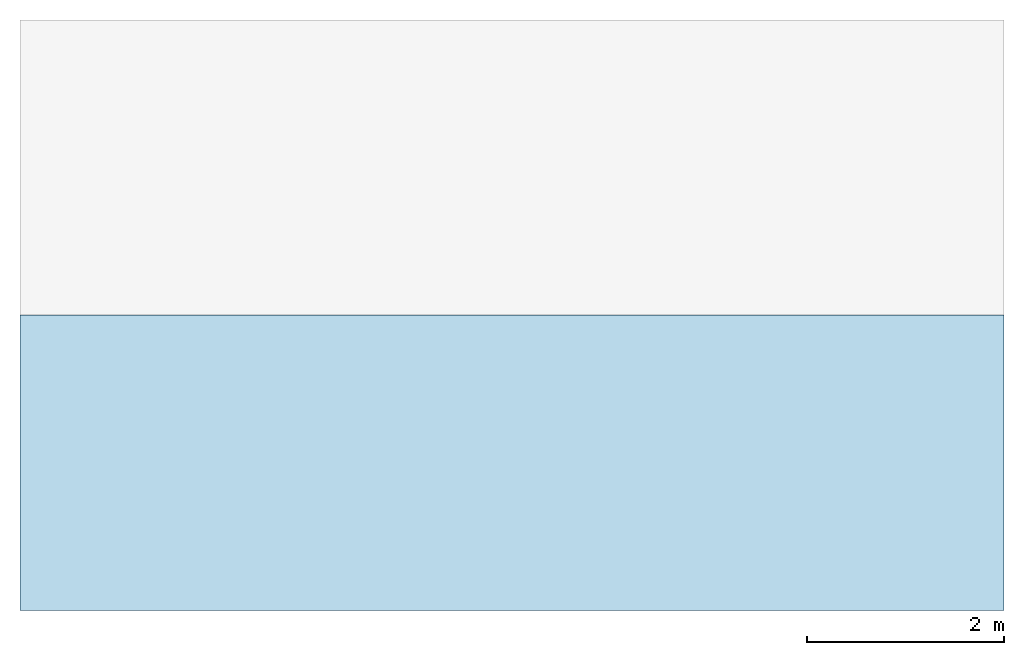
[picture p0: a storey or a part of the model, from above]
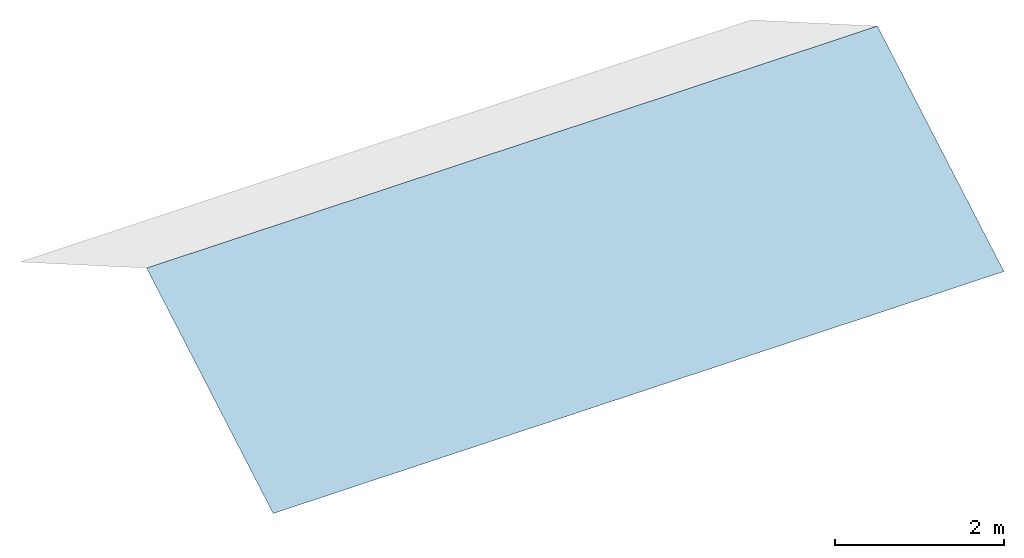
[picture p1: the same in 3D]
Properties of the parts of a building model (IFC4X3_ADD2)

# File
Description: StrechoStav Sketch IFC export
File name: Sk-obn-sedlov-strecha.ifc
Time: 2026-08-17T10:00:00Z
Organization: StrechoStav
Written by: StrechoStav Sketch 3.7.55
Made in: StrechoStav Sketch

# IfcProject: STRECHOSTAV_PROJECT, Skúšobná sedlová strecha
Description: StrechoStav Sketch BIM export; LongName: Skúšobná sedlová strecha
StrechoStav_ProjectData - Schema: strechostav-sketch-project-6; SchemaVersion: 6; Application: StrechoStav Sketch; ApplicationVersion: 3.7.55; ProjectId: ifc-test-project; PayloadEncoding: UTF-8 JSON; PayloadSha256: 6aeb4ea7a81c1e32eb3cb1a4cec82e20a06544cac115e883fd99c32776cfce77; PayloadChunkCount: 4; Payload0001: { "schema": "strechostav-sketch-project-10", "attic_height_m": 0.3, "roof_topology": { "schema_version": 3, "nodes": [ { "x": 0, "y": 0, "id": "A", "type": "FOOTPRINT", "locked": false }, { "x": 10, "y": 0, "id": "B", "type": "FOOTPRINT", "locked": false }, { "x": 10, "y": 6, "id": "C", "type": "FOOTPRINT", "locked": false }, { "x": 0, "y": 6, "id": "D", "type": "FOOTPRINT", "locked": false }, { "x": 0, "y": 3, "id": "L", "type": "FOOTPRINT", "locked": false }, { "x": 10, "y": 3, "id": "R", "type": "FOOTPRINT", "locked": false } ], "origin": { "lon": 18, "lat": 49 }, "edges": [ { "boundary": true, "note": "", "end_node_id": "B", "id": "AB", "start_node_id": "A", "source_id": "AB", "type": "EAVE", "locked": false }, { "boundary": true, "note": "", "end_node_id": "R", "id": "BR", "start_node_id": "B", "source_id": "BR", "type": "GABLE", "locked": false }, { "boundary": true, "note": "", "end_node_id": "D", "id": "CD", "start_node_id": "C", "source_id": "CD", "type": "EAVE", "locked": false }, { "boundary": true, "note": "", "end_node_id": "L", "id": "DL", "start_node_id": "D", "source_id": "DL", "type": "GABLE", "locked": false }, { "boundary": true, "note": "", "end_node_id": "A", "id": "LA", "start_node_id": "L", "source_id": "LA", "type": "GABLE", "locked": false }, { "boundary": true, "note": "", "end_node_id": "C", "id": "RC", "start_node_id": "R", "source_id": "RC", "type": "GABLE", "locked": false }, { "boundary": false, "note": "", "end_node_id": "R", "id": "RIDGE", "start_node_id": "L", "source_id": "RIDGE", "type": "RIDGE", "locked": false } ], "grid_rotation_deg": 0 }, "wall_height_m": 3, "objects": [ { "downspout_suppressed": false, "note": "", "direction_x": 0, "direction_y": 1, "center": { "lon": 18.000068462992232, "lat": 49.000013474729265 }, "downspout_termination": "ELBOW_72", "width_mm": 780, "downspout_automatic": false, "type": "ROOF_WINDOW", "dormer_overhang_mm": 250, "rotation_deg": 0, "dormer_type": "GABLE", "superstructure_height_m": 1.2,; Payload0002: "superstructure_slope_deg": 15, "chimney_height_manual": false, "attached_face_id": "face-105dda3c-4227-3e2c-8284-361fde8efe1c", "id": "window-1", "height_mm": 1180, "diameter_mm": 0, "value": 0 }, { "downspout_suppressed": false, "note": "", "direction_x": 0, "direction_y": 1, "center": { "lon": 18.000027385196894, "lat": 49.00004042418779 }, "downspout_termination": "ELBOW_72", "width_mm": 700, "downspout_automatic": false, "type": "CHIMNEY", "dormer_overhang_mm": 250, "rotation_deg": 0, "dormer_type": "GABLE", "superstructure_height_m": 1.2, "superstructure_slope_deg": 15, "chimney_height_manual": false, "attached_face_id": "face-7f29ebdd-5568-3a92-861d-d7df8271fc61", "id": "chimney-1", "height_mm": 700, "diameter_mm": 0, "value": 1.2 } ], "created_at": 1700000000000, "wall_footprint_parts": [], "underlay_meters_per_pixel": 0.01, "underlay_zoom": 1, "schema_version": 10, "map_type": "ZBGIS_ORTHO", "underlay_uri": "", "geometry_grid_origin_lat": 49, "updated_at": 1700000000000, "budget_vat_percent": 23, "roof_shape": "GABLE", "roof_graph": { "schema_version": 2, "components": [{ "face_ids": [], "id": "main", "label": "Hlavná strecha" }], "nodes": [ { "lock_z": false, "lock_x": false, "lock_y": false, "x": 0, "y": 0, "z": 0, "id": "A" }, { "lock_z": false, "lock_x": false, "lock_y": false, "x": 10, "y": 0, "z": 0, "id": "B" }, { "lock_z": false, "lock_x": false, "lock_y": false, "x": 10, "y": 6, "z": 0, "id": "C" }, { "lock_z": false, "lock_x": false, "lock_y": false, "x": 0, "y": 6, "z": 0, "id": "D" }, { "lock_z": false, "lock_x": false, "lock_y": false, "x": 0, "y": 3, "z": 0, "id": "L" }, { "lock_z": false, "lock_x": false, "lock_y": false, "x": 10, "y": 3, "z": 0, "id": "R" } ], "origin": { "lon": 18, "lat": 49 }, "edges": [ { "boundary": true, "note": "", "end_node_id": "B", "id": "AB", "start_node_id": "A", "semantic_role": "EAVE", "locked": false, "adjacent_face_ids": ["face-7f29ebdd-5568-3a92-861d-d7df8271fc61"] }, { "boundary": true, "note": "", "end_node_id": "R", "id": "BR", "start_node_id": "B", "semantic_role": "GABLE", "locked": false, "adjacent_face_ids": ["face-7f29ebdd-5568-3a92-861d-d7df8271fc61"] }; Payload0003: , { "boundary": true, "note": "", "end_node_id": "D", "id": "CD", "start_node_id": "C", "semantic_role": "EAVE", "locked": false, "adjacent_face_ids": ["face-105dda3c-4227-3e2c-8284-361fde8efe1c"] }, { "boundary": true, "note": "", "end_node_id": "L", "id": "DL", "start_node_id": "D", "semantic_role": "GABLE", "locked": false, "adjacent_face_ids": ["face-105dda3c-4227-3e2c-8284-361fde8efe1c"] }, { "boundary": true, "note": "", "end_node_id": "A", "id": "LA", "start_node_id": "L", "semantic_role": "GABLE", "locked": false, "adjacent_face_ids": ["face-7f29ebdd-5568-3a92-861d-d7df8271fc61"] }, { "boundary": true, "note": "", "end_node_id": "C", "id": "RC", "start_node_id": "R", "semantic_role": "GABLE", "locked": false, "adjacent_face_ids": ["face-105dda3c-4227-3e2c-8284-361fde8efe1c"] }, { "boundary": false, "note": "", "end_node_id": "R", "id": "RIDGE", "start_node_id": "L", "semantic_role": "RIDGE", "locked": false, "adjacent_face_ids": [ "face-105dda3c-4227-3e2c-8284-361fde8efe1c", "face-7f29ebdd-5568-3a92-861d-d7df8271fc61" ] } ], "edge_length_constraints": [], "faces": [ { "ordered_edge_ids": [ "CD", "DL", "RIDGE", "RC" ], "hole_node_id_loops": [], "component_id": "main", "underconstrained": false, "ordered_node_ids": [ "C", "D", "L", "R" ], "signed_area_m2": 30, "id": "face-105dda3c-4227-3e2c-8284-361fde8efe1c", "elevation_constraints": [] }, { "ordered_edge_ids": [ "AB", "BR", "RIDGE", "LA" ], "hole_node_id_loops": [], "component_id": "main", "underconstrained": false, "ordered_node_ids": [ "A", "B", "R", "L" ], "signed_area_m2": 30, "id": "face-7f29ebdd-5568-3a92-861d-d7df8271fc61", "elevation_constraints": [] } ], "grid_rotation_deg": 0, "drain_point_constraints": [], "dimensions": [] }, "slope_deg": 30, "id": "ifc-test-project", "lines": [], "last_google_map_type": "ZBGIS_ORTHO", "summary": { "perimeter_m": 33.856406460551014, "wall_end_m": 0, "superstructure_roof_area_m2": 0, "height_marks": 0, "superstructure_opening_area_m2": 0, "gable_m": 13.856406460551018, "hip_m": 0, "outer_gutter_corners_90": 0, "terraces": 0, "shafts": 0, "roof_area_m2": 69.28203230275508, "eave_m": 20, "machine_rooms": 0, "drains"; Payload0004: : 0, "gutter_hooks": 26, "chimneys": 1, "inner_gutter_corners_90": 0, "attic_m": 0, "downspout_clamps": 6, "vents": 0, "hatches": 0, "dormers": 0, "downspouts": 2, "slope_marks": 0, "roof_windows": 1, "footprint_area_m2": 60, "valley_m": 0, "pult_m": 0, "ridge_m": 10 }, "address": "Martin, Slovensko", "underlay_mime": "", "attic_width_m": 0.25, "underlay_center_x": -1, "center_lon": 18.9236, "underlay_center_y": -1, "underlay_origin_lon": 18.9236, "zoom": 19, "edge_types": {}, "geometry_grid_rotation_deg": 0, "selected_work_items": [], "center_lat": 49.0663, "wall_footprint": [ { "lon": 18, "lat": 49 }, { "lon": 18.000136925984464, "lat": 49 }, { "lon": 18.000136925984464, "lat": 49.00002694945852 }, { "lon": 18.000136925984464, "lat": 49.000053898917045 }, { "lon": 18, "lat": 49.000053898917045 }, { "lon": 18, "lat": 49.00002694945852 } ], "map_rotation_deg": 0, "polygon": [ { "lon": 18, "lat": 49 }, { "lon": 18.000136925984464, "lat": 49 }, { "lon": 18.000136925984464, "lat": 49.00002694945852 }, { "lon": 18.000136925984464, "lat": 49.000053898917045 }, { "lon": 18, "lat": 49.000053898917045 }, { "lon": 18, "lat": 49.00002694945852 } ], "underlay_origin_lat": 49.0663, "name": "Skúšobná sedlová strecha", "underlay_name": "", "wall_footprint_parts_signature": "", "geometry_grid_origin_lon": 18, "customer": "Žofia O'Connor" }

# IfcBuilding, Skúšobná sedlová strecha
LongName: Skúšobná sedlová strecha

# IfcBuildingStorey, Strecha
In: Skúšobná sedlová strecha
LongName: Strecha; Elevation: 3 m

# IfcChimney: CHIMNEY, Komín
In: Strecha
StrechoStav_Object - ObjectId: chimney-1; ObjectType: CHIMNEY; WidthMm: 700; HeightMm: 700; Value: 1.2; RotationDeg: 0; AttachedFaceId: face-7f29ebdd-5568-3a92-861d-d7df8271fc61; DirectionX: 0; DirectionY: 1; ChimneyHeightManual: no

# IfcOpeningElement: ROOF_WINDOW_OPENING, Otvor pre strešné okno window-1
In: Strecha
PredefinedType: OPENING

# IfcRoof: GABLE, Strecha
In: Strecha
PredefinedType: GABLE_ROOF
StrechoStav_Roof - ProjectId: ifc-test-project; RoofShape: GABLE; DefaultSlopeDeg: 30; WallHeightM: 3; OriginLatitude: 49; OriginLongitude: 18; GraphEdgesJson: [{"id":"AB","role":"EAVE","start":"A","end":"B"}, {"id":"BR","role":"GABLE","start":"B","end":"R"}, {"id":"CD","role":"EAVE","start":"C","end":"D"}, {"id":"DL","role":"GABLE","start":"D","end":"L"}, {"id":"LA","role":"GABLE","start":"L","end":"A"}, {"id":"RC","role":"GABLE","start":"R","end":"C"}, {"id":"RIDGE","role":"RIDGE","start":"L","end":"R"}]
Qto_RoofBaseQuantities - GrossArea: 69.282 m2; NetArea: 69.282 m2; ProjectedArea: 60 m2

# IfcSlab: ROOF_FACE (2)
In: Strecha
PredefinedType: ROOF
StrechoStav_RoofFace - ComponentId: main; PlaneA: 0; Underconstrained: no; PlanAreaM2: 30; Area3DM2: 34.641; SlopeConstraintAngleDeg: 30; SlopeDirectionX: 0; SlopeConstraintHard: yes
Qto_SlabBaseQuantities - Perimeter: 26.9282 m; GrossArea: 34.641 m2; NetArea: 34.641 m2
Name | ObjectId | FaceId | PlaneB | PlaneC | OrderedNodeIds | OrderedEdgeIds | SlopeDirectionY
Strešná plocha face-105dda3c-4227-3e2c-8284-361fde8efe1c | face:ifc-test-project:face-105dda3c-4227-3e2c-8284-361fde8efe1c | face-105dda3c-4227-3e2c-8284-361fde8efe1c | -0.57735 | 6.4641 | C,D,L,R | CD,DL,RIDGE,RC | 1
Strešná plocha face-7f29ebdd-5568-3a92-861d-d7df8271fc61 | face:ifc-test-project:face-7f29ebdd-5568-3a92-861d-d7df8271fc61 | face-7f29ebdd-5568-3a92-861d-d7df8271fc61 | 0.57735 | 3 | A,B,R,L | AB,BR,RIDGE,LA | -1

# IfcWindow: ROOF_WINDOW, Strešné okno
In: Strecha
OverallHeight: 1.18 m; OverallWidth: 0.78 m; PredefinedType: WINDOW
StrechoStav_Object - ObjectId: window-1; ObjectType: ROOF_WINDOW; WidthMm: 780; HeightMm: 1180; RotationDeg: 0; AttachedFaceId: face-105dda3c-4227-3e2c-8284-361fde8efe1c; DirectionX: 0; DirectionY: 1; ChimneyHeightManual: no
